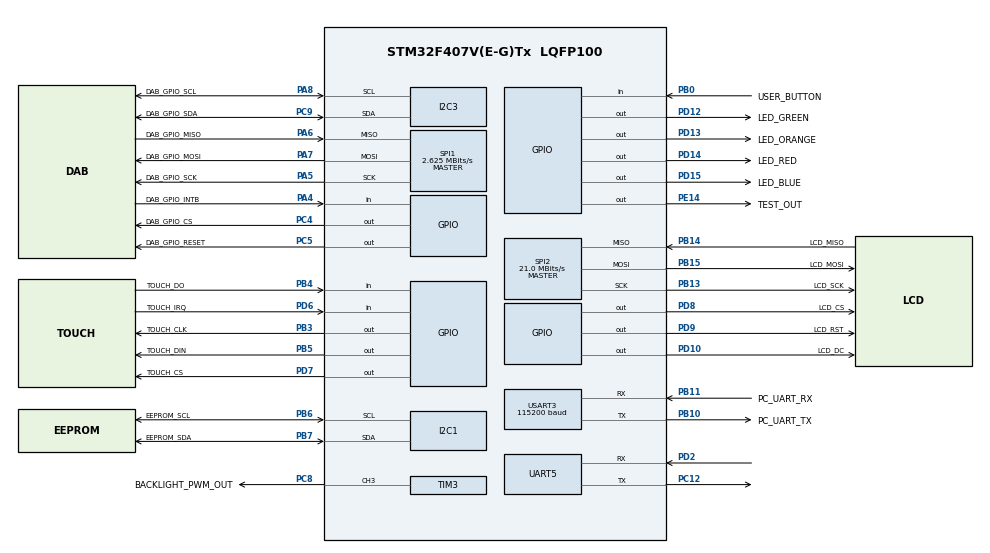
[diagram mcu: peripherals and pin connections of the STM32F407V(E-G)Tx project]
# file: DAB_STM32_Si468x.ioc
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Dma.Request0=SPI2_TX
Dma.SPI2_TX.0.Direction=DMA_MEMORY_TO_PERIPH
Dma.SPI2_TX.0.FIFOMode=DMA_FIFOMODE_DISABLE
Dma.SPI2_TX.0.Instance=DMA1_Stream4
Dma.SPI2_TX.0.MemDataAlignment=DMA_MDATAALIGN_BYTE
Dma.SPI2_TX.0.MemInc=DMA_MINC_ENABLE
Dma.SPI2_TX.0.Mode=DMA_NORMAL
Dma.SPI2_TX.0.PeriphDataAlignment=DMA_PDATAALIGN_BYTE
Dma.SPI2_TX.0.PeriphInc=DMA_PINC_DISABLE
Dma.SPI2_TX.0.Priority=DMA_PRIORITY_LOW
I2C1.I2C_Mode=I2C_Standard
Mcu.Family=STM32F4
Mcu.Name=STM32F407V(E-G)Tx
Mcu.Package=LQFP100
NVIC.DMA1_Stream4_IRQn=true\:0\:0\:false\:false\:true\:false\:true\:true
NVIC.I2C3_ER_IRQn=true\:0\:0\:false\:false\:true\:true\:true\:true
NVIC.I2C3_EV_IRQn=true\:0\:0\:false\:false\:true\:true\:true\:true
NVIC.PriorityGroup=NVIC_PRIORITYGROUP_4
NVIC.SPI2_IRQn=true\:0\:0\:false\:false\:true\:true\:true\:true
NVIC.TIM1_TRG_COM_TIM11_IRQn=true\:0\:0\:false\:false\:true\:true\:true\:true
NVIC.TIM1_UP_TIM10_IRQn=true\:0\:0\:false\:false\:true\:true\:true\:true
PA4.GPIO_Label=DAB_GPIO_INTB
PA4.Signal=GPIO_Input
PA5.GPIO_Label=DAB_GPIO_SCK
PA5.Mode=Full_Duplex_Master
PA5.Signal=SPI1_SCK
PA6.GPIO_Label=DAB_GPIO_MISO
PA6.Mode=Full_Duplex_Master
PA6.Signal=SPI1_MISO
PA7.GPIO_Label=DAB_GPIO_MOSI
PA7.Mode=Full_Duplex_Master
PA7.Signal=SPI1_MOSI
PA8.GPIO_Label=DAB_GPIO_SCL
PA8.Mode=I2C
PA8.Signal=I2C3_SCL
PB0.GPIO_Label=USER_BUTTON
PB0.Signal=GPIO_Input
PB10.GPIO_Label=PC_UART_TX
PB10.Mode=Asynchronous
PB10.Signal=USART3_TX
PB11.GPIO_Label=PC_UART_RX
PB11.Mode=Asynchronous
PB11.Signal=USART3_RX
PB13.GPIO_Label=LCD_SCK
PB13.Mode=Full_Duplex_Master
PB13.Signal=SPI2_SCK
PB14.GPIO_Label=LCD_MISO
PB14.Mode=Full_Duplex_Master
PB14.Signal=SPI2_MISO
PB15.GPIO_Label=LCD_MOSI
PB15.Mode=Full_Duplex_Master
PB15.Signal=SPI2_MOSI
PB3.GPIO_Label=TOUCH_CLK
PB3.GPIO_Speed=GPIO_SPEED_FREQ_HIGH
PB3.Signal=GPIO_Output
PB4.GPIO_Label=TOUCH_DO
PB4.Signal=GPIO_Input
PB5.GPIO_Label=TOUCH_DIN
PB5.GPIO_Speed=GPIO_SPEED_FREQ_HIGH
PB5.Signal=GPIO_Output
PB6.GPIO_Label=EEPROM_SCL
PB6.Mode=I2C
PB6.Signal=I2C1_SCL
PB7.GPIO_Label=EEPROM_SDA
PB7.Mode=I2C
PB7.Signal=I2C1_SDA
PC12.Mode=Asynchronous
PC12.Signal=UART5_TX
PC4.GPIO_Label=DAB_GPIO_CS
PC4.GPIO_Speed=GPIO_SPEED_FREQ_HIGH
PC4.Signal=GPIO_Output
PC5.GPIO_Label=DAB_GPIO_RESET
PC5.GPIO_Speed=GPIO_SPEED_FREQ_HIGH
PC5.Signal=GPIO_Output
PC8.GPIO_Label=BACKLIGHT_PWM_OUT
PC8.Signal=S_TIM3_CH3
PC9.GPIO_Label=DAB_GPIO_SDA
PC9.Mode=I2C
PC9.Signal=I2C3_SDA
PD10.GPIO_Label=LCD_DC
PD10.GPIO_Speed=GPIO_SPEED_FREQ_HIGH
PD10.Signal=GPIO_Output
PD12.GPIO_Label=LED_GREEN
PD12.Signal=GPIO_Output
PD13.GPIO_Label=LED_ORANGE
PD13.Signal=GPIO_Output
PD14.GPIO_Label=LED_RED
PD14.Signal=GPIO_Output
PD15.GPIO_Label=LED_BLUE
PD15.Signal=GPIO_Output
PD2.Mode=Asynchronous
PD2.Signal=UART5_RX
PD6.GPIO_Label=TOUCH_IRQ
PD6.Signal=GPIO_Input
PD7.GPIO_Label=TOUCH_CS
PD7.GPIO_Speed=GPIO_SPEED_FREQ_HIGH
PD7.Signal=GPIO_Output
PD8.GPIO_Label=LCD_CS
PD8.GPIO_Speed=GPIO_SPEED_FREQ_HIGH
PD8.Signal=GPIO_Output
PD9.GPIO_Label=LCD_RST
PD9.GPIO_Speed=GPIO_SPEED_FREQ_HIGH
PD9.Signal=GPIO_Output
PE14.GPIO_Label=TEST_OUT
PE14.Signal=GPIO_Output
PH0-OSC_IN.Mode=HSE-External-Oscillator
PH0-OSC_IN.Signal=RCC_OSC_IN
PH1-OSC_OUT.Mode=HSE-External-Oscillator
PH1-OSC_OUT.Signal=RCC_OSC_OUT
ProjectManager.HeapSize=0x200
ProjectManager.StackSize=0x400
ProjectManager.TargetToolchain=STM32CubeIDE
RCC.48MHZClocksFreq_Value=84000000
RCC.AHBFreq_Value=168000000
RCC.APB1CLKDivider=RCC_HCLK_DIV4
RCC.APB1Freq_Value=42000000
RCC.APB1TimFreq_Value=84000000
RCC.APB2CLKDivider=RCC_HCLK_DIV2
RCC.APB2Freq_Value=84000000
RCC.APB2TimFreq_Value=168000000
RCC.CortexFreq_Value=168000000
RCC.HCLKFreq_Value=168000000
RCC.HSE_VALUE=8000000
RCC.HSI_VALUE=16000000
RCC.LSE_VALUE=32768
RCC.PLLM=4
RCC.PLLN=168
RCC.PLLSourceVirtual=RCC_PLLSOURCE_HSE
RCC.SYSCLKFreq_VALUE=168000000
RCC.SYSCLKSource=RCC_SYSCLKSOURCE_PLLCLK
RCC.VCOOutputFreq_Value=336000000
SH.S_TIM3_CH3.0=TIM3_CH3,PWM Generation3 CH3
SPI1.BaudRatePrescaler=SPI_BAUDRATEPRESCALER_32
SPI1.CLKPhase=SPI_PHASE_1EDGE
SPI1.CLKPolarity=SPI_POLARITY_LOW
SPI1.CalculateBaudRate=2.625 MBits/s
SPI1.Direction=SPI_DIRECTION_2LINES
SPI1.Mode=SPI_MODE_MASTER
SPI1.VirtualType=VM_MASTER
SPI2.CalculateBaudRate=21.0 MBits/s
SPI2.Direction=SPI_DIRECTION_2LINES
SPI2.Mode=SPI_MODE_MASTER
SPI2.VirtualType=VM_MASTER
TIM10.Period=599
TIM10.Prescaler=14999
TIM11.Period=1299
TIM11.Prescaler=14999
TIM3.Channel-PWM\ Generation3\ CH3=TIM_CHANNEL_3
UART5.VirtualMode=Asynchronous
USART3.BaudRate=115200
USART3.VirtualMode=VM_ASYNC
VP_TIM10_VS_ClockSourceINT.Mode=Enable_Timer
VP_TIM11_VS_ClockSourceINT.Mode=Enable_Timer
board=custom

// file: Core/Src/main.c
/* USER CODE BEGIN Header */
/**
  ******************************************************************************
  * @file           : main.c
  * @brief          : Main program body
  ******************************************************************************
  * @attention
  *
  * Copyright (c) 2022 STMicroelectronics.
  * All rights reserved.
  *
  * This software is licensed under terms that can be found in the LICENSE file
  * in the root directory of this software component.
  * If no LICENSE file comes with this software, it is provided AS-IS.
  *
  ******************************************************************************
  */
/* USER CODE END Header */
#include "main.h"
#include "dma.h"
#include "i2c.h"
#include "spi.h"
#include "tim.h"
#include "usart.h"
#include "gpio.h"

/* USER CODE BEGIN Includes */
#include "Si468x.h"
#include "debug_uart.h"
#include "touch.h"
#include "state_machine.h"
#include "eeprom.h"
#include "ILI9341_Driver.h"
#include "dab_defs.h"
/* USER CODE END Includes */

void SystemClock_Config(void);

int main(void)
{

  /* MCU Configuration--------------------------------------------------------*/

  /* Reset of all peripherals, Initializes the Flash interface and the Systick. */
  HAL_Init();

  /* Configure the system clock */
  SystemClock_Config();

  /* Initialize all configured peripherals */
  MX_GPIO_Init();
  MX_DMA_Init();
  MX_I2C1_Init();
  MX_I2C3_Init();
  MX_SPI1_Init();
  MX_SPI2_Init();
  MX_TIM3_Init();
  MX_UART5_Init();
  MX_USART3_UART_Init();
  MX_TIM10_Init();
  MX_TIM11_Init();
  /* USER CODE BEGIN 2 */
  send_debug_msg("STM32 is ready.", CRLF_SEND);

  HAL_TIM_Base_Start_IT(&htim11);

  ILI9341_Init();
  Display_booting_screen();

  //check_eeprom_erased();
  //HAL_Delay(5000);

  //eeprom_erase();

  //eeprom_show();

  //HAL_Delay(50000);

  Si468x_dab_init();
  restore_from_eeprom();

  /* USER CODE END 2 */

  /* Infinite loop */
  /* USER CODE BEGIN WHILE */
  while (1)
  {
	  state_machine();

    /* USER CODE END WHILE */

  }
}

void SystemClock_Config(void)
{
  RCC_OscInitTypeDef RCC_OscInitStruct = {0};
  RCC_ClkInitTypeDef RCC_ClkInitStruct = {0};

  /** Configure the main internal regulator output voltage
  */
  __HAL_RCC_PWR_CLK_ENABLE();
  __HAL_PWR_VOLTAGESCALING_CONFIG(PWR_REGULATOR_VOLTAGE_SCALE1);

  /** Initializes the RCC Oscillators according to the specified parameters
  * in the RCC_OscInitTypeDef structure.
  */
  RCC_OscInitStruct.OscillatorType = RCC_OSCILLATORTYPE_HSE;
  RCC_OscInitStruct.HSEState = RCC_HSE_ON;
  RCC_OscInitStruct.PLL.PLLState = RCC_PLL_ON;
  RCC_OscInitStruct.PLL.PLLSource = RCC_PLLSOURCE_HSE;
  RCC_OscInitStruct.PLL.PLLM = 4;
  RCC_OscInitStruct.PLL.PLLN = 240;
  RCC_OscInitStruct.PLL.PLLP = RCC_PLLP_DIV2;
  RCC_OscInitStruct.PLL.PLLQ = 4;
  if (HAL_RCC_OscConfig(&RCC_OscInitStruct) != HAL_OK)
  {
    Error_Handler();
  }

  /** Initializes the CPU, AHB and APB buses clocks
  */
  RCC_ClkInitStruct.ClockType = RCC_CLOCKTYPE_HCLK|RCC_CLOCKTYPE_SYSCLK
                              |RCC_CLOCKTYPE_PCLK1|RCC_CLOCKTYPE_PCLK2;
  RCC_ClkInitStruct.SYSCLKSource = RCC_SYSCLKSOURCE_PLLCLK;
  RCC_ClkInitStruct.AHBCLKDivider = RCC_SYSCLK_DIV1;
  RCC_ClkInitStruct.APB1CLKDivider = RCC_HCLK_DIV4;
  RCC_ClkInitStruct.APB2CLKDivider = RCC_HCLK_DIV2;

  if (HAL_RCC_ClockConfig(&RCC_ClkInitStruct, FLASH_LATENCY_5) != HAL_OK)
  {
    Error_Handler();
  }
}

void Error_Handler(void)
{
  __disable_irq();
  while (1)
  {
  }
}
